VERSION 5.7 ;
  NOWIREEXTENSIONATPIN ON ;
  DIVIDERCHAR "/" ;
  BUSBITCHARS "[]" ;
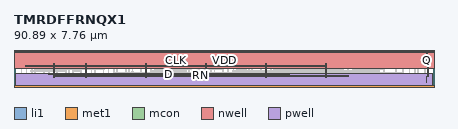
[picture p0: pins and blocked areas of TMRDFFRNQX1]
MACRO TMRDFFRNQX1
  CLASS CORE ;
  FOREIGN TMRDFFRNQX1 ;
  ORIGIN 0.000 0.000 ;
  SIZE 90.890 BY 7.760 ;
  SYMMETRY X Y ;
  SITE unitrh ;
  PIN Q
    DIRECTION OUTPUT ;
    USE SIGNAL ;
    ANTENNADIFFAREA 0.771900 ;
    PORT
      LAYER li1 ;
        RECT 89.210 4.845 89.380 7.200 ;
        RECT 89.210 4.675 89.745 4.845 ;
        RECT 89.575 2.345 89.745 4.675 ;
        RECT 89.205 2.175 89.745 2.345 ;
        RECT 89.205 1.020 89.375 2.175 ;
    END
  END Q
  PIN D
    DIRECTION INPUT ;
    USE SIGNAL ;
    ANTENNAGATEAREA 3.044550 ;
    PORT
      LAYER met1 ;
        RECT 7.405 2.855 7.635 2.885 ;
        RECT 33.305 2.855 33.535 2.885 ;
        RECT 59.205 2.855 59.435 2.885 ;
        RECT 7.375 2.685 59.585 2.855 ;
        RECT 7.405 2.655 7.635 2.685 ;
        RECT 33.305 2.655 33.535 2.685 ;
        RECT 59.205 2.655 59.435 2.685 ;
    END
  END D
  PIN CLK
    DIRECTION INPUT ;
    USE SIGNAL ;
    ANTENNAGATEAREA 6.089100 ;
    PORT
      LAYER met1 ;
        RECT 2.595 4.705 2.825 4.735 ;
        RECT 15.545 4.705 15.775 4.735 ;
        RECT 28.495 4.705 28.725 4.735 ;
        RECT 41.445 4.705 41.675 4.735 ;
        RECT 54.395 4.705 54.625 4.735 ;
        RECT 67.345 4.705 67.575 4.735 ;
        RECT 2.565 4.535 67.605 4.705 ;
        RECT 2.595 4.505 2.825 4.535 ;
        RECT 15.545 4.505 15.775 4.535 ;
        RECT 28.495 4.505 28.725 4.535 ;
        RECT 41.445 4.505 41.675 4.535 ;
        RECT 54.395 4.505 54.625 4.535 ;
        RECT 67.345 4.505 67.575 4.535 ;
    END
    PORT
      LAYER li1 ;
        RECT 15.575 2.095 15.745 5.045 ;
      LAYER mcon ;
        RECT 15.575 4.535 15.745 4.705 ;
    END
    PORT
      LAYER li1 ;
        RECT 28.525 2.095 28.695 5.045 ;
      LAYER mcon ;
        RECT 28.525 4.535 28.695 4.705 ;
    END
    PORT
      LAYER li1 ;
        RECT 41.475 2.095 41.645 5.045 ;
      LAYER mcon ;
        RECT 41.475 4.535 41.645 4.705 ;
    END
    PORT
      LAYER li1 ;
        RECT 54.425 2.095 54.595 5.045 ;
      LAYER mcon ;
        RECT 54.425 4.535 54.595 4.705 ;
    END
    PORT
      LAYER li1 ;
        RECT 67.375 2.095 67.545 5.045 ;
      LAYER mcon ;
        RECT 67.375 4.535 67.545 4.705 ;
    END
  END CLK
  PIN RN
    DIRECTION INPUT ;
    USE SIGNAL ;
    ANTENNAGATEAREA 9.208050 ;
    PORT
      LAYER met1 ;
        RECT 8.515 2.485 8.745 2.515 ;
        RECT 16.655 2.485 16.885 2.515 ;
        RECT 20.355 2.485 20.585 2.515 ;
        RECT 34.415 2.485 34.645 2.515 ;
        RECT 42.555 2.485 42.785 2.515 ;
        RECT 46.255 2.485 46.485 2.515 ;
        RECT 60.315 2.485 60.545 2.515 ;
        RECT 68.455 2.485 68.685 2.515 ;
        RECT 72.155 2.485 72.385 2.515 ;
        RECT 8.485 2.315 72.415 2.485 ;
        RECT 8.515 2.285 8.745 2.315 ;
        RECT 16.655 2.285 16.885 2.315 ;
        RECT 20.355 2.285 20.585 2.315 ;
        RECT 34.415 2.285 34.645 2.315 ;
        RECT 42.555 2.285 42.785 2.315 ;
        RECT 46.255 2.285 46.485 2.315 ;
        RECT 60.315 2.285 60.545 2.315 ;
        RECT 68.455 2.285 68.685 2.315 ;
        RECT 72.155 2.285 72.385 2.315 ;
    END
    PORT
      LAYER li1 ;
        RECT 8.545 2.095 8.715 5.045 ;
      LAYER mcon ;
        RECT 8.545 2.315 8.715 2.485 ;
    END
  END RN
  PIN VDD
    DIRECTION INOUT ;
    USE POWER ;
    SHAPE ABUTMENT ;
    PORT
      LAYER nwell ;
        RECT 0.000 4.110 90.890 7.940 ;
      LAYER met1 ;
        RECT 0.000 7.410 90.890 7.760 ;
    END
  END VDD
  PIN GND
    DIRECTION INOUT ;
    USE GROUND ;
    SHAPE ABUTMENT ;
    PORT
      LAYER pwell ;
        RECT 0.320 0.000 90.570 2.900 ;
      LAYER met1 ;
        RECT 0.000 0.000 90.890 0.350 ;
    END
  END GND
  OBS
      LAYER li1 ;
        RECT 0.000 7.410 90.890 7.760 ;
        RECT 0.320 4.290 0.660 7.410 ;
        RECT 1.495 5.395 1.665 7.410 ;
        RECT 1.935 5.420 2.105 7.200 ;
        RECT 2.375 5.735 2.545 7.410 ;
        RECT 2.815 5.420 2.985 7.200 ;
        RECT 3.255 5.735 3.425 7.410 ;
        RECT 3.695 5.420 3.865 7.200 ;
        RECT 4.135 5.735 4.305 7.410 ;
        RECT 1.935 5.250 4.645 5.420 ;
        RECT 0.320 0.350 0.660 2.900 ;
        RECT 1.515 2.095 1.685 5.045 ;
        RECT 2.625 2.095 2.795 5.045 ;
        RECT 3.735 2.095 3.905 5.045 ;
        RECT 0.995 1.855 1.165 1.935 ;
        RECT 1.965 1.855 2.135 1.935 ;
        RECT 2.935 1.855 3.105 1.935 ;
        RECT 0.995 1.685 3.105 1.855 ;
        RECT 0.995 0.555 1.165 1.685 ;
        RECT 1.480 0.350 1.650 1.310 ;
        RECT 1.965 0.805 2.135 1.685 ;
        RECT 2.935 1.605 3.105 1.685 ;
        RECT 2.455 1.260 2.625 1.340 ;
        RECT 3.505 1.260 3.675 1.935 ;
        RECT 4.475 1.930 4.645 5.250 ;
        RECT 5.130 4.290 5.470 7.410 ;
        RECT 6.305 5.395 6.475 7.410 ;
        RECT 6.745 5.420 6.915 7.200 ;
        RECT 7.185 5.735 7.355 7.410 ;
        RECT 7.625 5.420 7.795 7.200 ;
        RECT 8.065 5.735 8.235 7.410 ;
        RECT 8.505 5.420 8.675 7.200 ;
        RECT 8.945 5.735 9.115 7.410 ;
        RECT 6.745 5.250 9.455 5.420 ;
        RECT 2.455 1.090 3.675 1.260 ;
        RECT 2.455 1.010 2.625 1.090 ;
        RECT 2.935 0.805 3.105 0.885 ;
        RECT 1.965 0.635 3.105 0.805 ;
        RECT 1.965 0.555 2.135 0.635 ;
        RECT 2.935 0.555 3.105 0.635 ;
        RECT 3.505 0.805 3.675 1.090 ;
        RECT 3.990 1.760 4.645 1.930 ;
        RECT 3.990 1.025 4.160 1.760 ;
        RECT 4.475 0.805 4.645 1.575 ;
        RECT 3.505 0.635 4.645 0.805 ;
        RECT 3.505 0.555 3.675 0.635 ;
        RECT 4.475 0.555 4.645 0.635 ;
        RECT 5.130 0.350 5.470 2.900 ;
        RECT 6.325 2.095 6.495 5.045 ;
        RECT 7.435 2.095 7.605 5.045 ;
        RECT 5.805 1.855 5.975 1.935 ;
        RECT 6.775 1.855 6.945 1.935 ;
        RECT 7.745 1.855 7.915 1.935 ;
        RECT 5.805 1.685 7.915 1.855 ;
        RECT 5.805 0.555 5.975 1.685 ;
        RECT 6.290 0.350 6.460 1.310 ;
        RECT 6.775 0.805 6.945 1.685 ;
        RECT 7.745 1.605 7.915 1.685 ;
        RECT 7.265 1.260 7.435 1.340 ;
        RECT 8.315 1.260 8.485 1.935 ;
        RECT 9.285 1.930 9.455 5.250 ;
        RECT 9.940 4.290 10.280 7.410 ;
        RECT 10.815 5.315 10.985 7.410 ;
        RECT 11.255 5.465 11.425 7.200 ;
        RECT 11.695 5.735 11.865 7.410 ;
        RECT 12.135 5.465 12.305 7.200 ;
        RECT 12.575 5.735 12.745 7.410 ;
        RECT 11.255 5.295 12.785 5.465 ;
        RECT 7.265 1.090 8.485 1.260 ;
        RECT 7.265 1.010 7.435 1.090 ;
        RECT 7.745 0.805 7.915 0.885 ;
        RECT 6.775 0.635 7.915 0.805 ;
        RECT 6.775 0.555 6.945 0.635 ;
        RECT 7.745 0.555 7.915 0.635 ;
        RECT 8.315 0.805 8.485 1.090 ;
        RECT 8.800 1.760 9.455 1.930 ;
        RECT 8.800 1.025 8.970 1.760 ;
        RECT 9.285 0.805 9.455 1.575 ;
        RECT 8.315 0.635 9.455 0.805 ;
        RECT 8.315 0.555 8.485 0.635 ;
        RECT 9.285 0.555 9.455 0.635 ;
        RECT 9.940 0.350 10.280 2.900 ;
        RECT 11.135 2.095 11.305 5.045 ;
        RECT 11.905 4.890 12.075 5.045 ;
        RECT 11.875 4.715 12.075 4.890 ;
        RECT 11.875 2.095 12.045 4.715 ;
        RECT 10.720 1.845 10.890 1.925 ;
        RECT 11.690 1.845 11.860 1.925 ;
        RECT 12.615 1.920 12.785 5.295 ;
        RECT 13.270 4.290 13.610 7.410 ;
        RECT 14.445 5.395 14.615 7.410 ;
        RECT 14.885 5.420 15.055 7.200 ;
        RECT 15.325 5.735 15.495 7.410 ;
        RECT 15.765 5.420 15.935 7.200 ;
        RECT 16.205 5.735 16.375 7.410 ;
        RECT 16.645 5.420 16.815 7.200 ;
        RECT 17.085 5.735 17.255 7.410 ;
        RECT 14.885 5.250 17.595 5.420 ;
        RECT 10.720 1.675 11.860 1.845 ;
        RECT 10.720 0.545 10.890 1.675 ;
        RECT 11.205 0.350 11.375 1.300 ;
        RECT 11.690 0.795 11.860 1.675 ;
        RECT 12.175 1.750 12.785 1.920 ;
        RECT 12.175 1.015 12.345 1.750 ;
        RECT 12.660 0.795 12.830 1.565 ;
        RECT 11.690 0.625 12.830 0.795 ;
        RECT 11.690 0.545 11.860 0.625 ;
        RECT 12.660 0.545 12.830 0.625 ;
        RECT 13.270 0.350 13.610 2.900 ;
        RECT 14.465 2.095 14.635 5.045 ;
        RECT 16.685 2.095 16.855 5.045 ;
        RECT 13.945 1.855 14.115 1.935 ;
        RECT 14.915 1.855 15.085 1.935 ;
        RECT 15.885 1.855 16.055 1.935 ;
        RECT 13.945 1.685 16.055 1.855 ;
        RECT 13.945 0.555 14.115 1.685 ;
        RECT 14.430 0.350 14.600 1.310 ;
        RECT 14.915 0.805 15.085 1.685 ;
        RECT 15.885 1.605 16.055 1.685 ;
        RECT 15.405 1.260 15.575 1.340 ;
        RECT 16.455 1.260 16.625 1.935 ;
        RECT 17.425 1.930 17.595 5.250 ;
        RECT 18.080 4.290 18.420 7.410 ;
        RECT 19.255 5.395 19.425 7.410 ;
        RECT 19.695 5.420 19.865 7.200 ;
        RECT 20.135 5.735 20.305 7.410 ;
        RECT 20.575 5.420 20.745 7.200 ;
        RECT 21.015 5.735 21.185 7.410 ;
        RECT 21.455 5.420 21.625 7.200 ;
        RECT 21.895 5.735 22.065 7.410 ;
        RECT 19.695 5.250 22.405 5.420 ;
        RECT 15.405 1.090 16.625 1.260 ;
        RECT 15.405 1.010 15.575 1.090 ;
        RECT 15.885 0.805 16.055 0.885 ;
        RECT 14.915 0.635 16.055 0.805 ;
        RECT 14.915 0.555 15.085 0.635 ;
        RECT 15.885 0.555 16.055 0.635 ;
        RECT 16.455 0.805 16.625 1.090 ;
        RECT 16.940 1.760 17.595 1.930 ;
        RECT 16.940 1.025 17.110 1.760 ;
        RECT 17.425 0.805 17.595 1.575 ;
        RECT 16.455 0.635 17.595 0.805 ;
        RECT 16.455 0.555 16.625 0.635 ;
        RECT 17.425 0.555 17.595 0.635 ;
        RECT 18.080 0.350 18.420 2.900 ;
        RECT 19.275 2.095 19.445 5.045 ;
        RECT 20.385 2.095 20.555 5.045 ;
        RECT 21.495 2.095 21.665 5.045 ;
        RECT 18.755 1.855 18.925 1.935 ;
        RECT 19.725 1.855 19.895 1.935 ;
        RECT 20.695 1.855 20.865 1.935 ;
        RECT 18.755 1.685 20.865 1.855 ;
        RECT 18.755 0.555 18.925 1.685 ;
        RECT 19.240 0.350 19.410 1.310 ;
        RECT 19.725 0.805 19.895 1.685 ;
        RECT 20.695 1.605 20.865 1.685 ;
        RECT 20.215 1.260 20.385 1.340 ;
        RECT 21.265 1.260 21.435 1.935 ;
        RECT 22.235 1.930 22.405 5.250 ;
        RECT 22.890 4.290 23.230 7.410 ;
        RECT 23.765 5.315 23.935 7.410 ;
        RECT 24.205 5.465 24.375 7.200 ;
        RECT 24.645 5.735 24.815 7.410 ;
        RECT 25.085 5.465 25.255 7.200 ;
        RECT 25.525 5.735 25.695 7.410 ;
        RECT 24.205 5.295 25.735 5.465 ;
        RECT 20.215 1.090 21.435 1.260 ;
        RECT 20.215 1.010 20.385 1.090 ;
        RECT 20.695 0.805 20.865 0.885 ;
        RECT 19.725 0.635 20.865 0.805 ;
        RECT 19.725 0.555 19.895 0.635 ;
        RECT 20.695 0.555 20.865 0.635 ;
        RECT 21.265 0.805 21.435 1.090 ;
        RECT 21.750 1.760 22.405 1.930 ;
        RECT 21.750 1.025 21.920 1.760 ;
        RECT 22.235 0.805 22.405 1.575 ;
        RECT 21.265 0.635 22.405 0.805 ;
        RECT 21.265 0.555 21.435 0.635 ;
        RECT 22.235 0.555 22.405 0.635 ;
        RECT 22.890 0.350 23.230 2.900 ;
        RECT 24.085 2.095 24.255 5.045 ;
        RECT 24.855 4.890 25.025 5.045 ;
        RECT 24.825 4.715 25.025 4.890 ;
        RECT 24.825 2.095 24.995 4.715 ;
        RECT 23.670 1.845 23.840 1.925 ;
        RECT 24.640 1.845 24.810 1.925 ;
        RECT 25.565 1.920 25.735 5.295 ;
        RECT 26.220 4.290 26.560 7.410 ;
        RECT 27.395 5.395 27.565 7.410 ;
        RECT 27.835 5.420 28.005 7.200 ;
        RECT 28.275 5.735 28.445 7.410 ;
        RECT 28.715 5.420 28.885 7.200 ;
        RECT 29.155 5.735 29.325 7.410 ;
        RECT 29.595 5.420 29.765 7.200 ;
        RECT 30.035 5.735 30.205 7.410 ;
        RECT 27.835 5.250 30.545 5.420 ;
        RECT 23.670 1.675 24.810 1.845 ;
        RECT 23.670 0.545 23.840 1.675 ;
        RECT 24.155 0.350 24.325 1.300 ;
        RECT 24.640 0.795 24.810 1.675 ;
        RECT 25.125 1.750 25.735 1.920 ;
        RECT 25.125 1.015 25.295 1.750 ;
        RECT 25.610 0.795 25.780 1.565 ;
        RECT 24.640 0.625 25.780 0.795 ;
        RECT 24.640 0.545 24.810 0.625 ;
        RECT 25.610 0.545 25.780 0.625 ;
        RECT 26.220 0.350 26.560 2.900 ;
        RECT 27.415 2.095 27.585 5.045 ;
        RECT 29.635 2.095 29.805 5.045 ;
        RECT 26.895 1.855 27.065 1.935 ;
        RECT 27.865 1.855 28.035 1.935 ;
        RECT 28.835 1.855 29.005 1.935 ;
        RECT 26.895 1.685 29.005 1.855 ;
        RECT 26.895 0.555 27.065 1.685 ;
        RECT 27.380 0.350 27.550 1.310 ;
        RECT 27.865 0.805 28.035 1.685 ;
        RECT 28.835 1.605 29.005 1.685 ;
        RECT 28.355 1.260 28.525 1.340 ;
        RECT 29.405 1.260 29.575 1.935 ;
        RECT 30.375 1.930 30.545 5.250 ;
        RECT 31.030 4.290 31.370 7.410 ;
        RECT 32.205 5.395 32.375 7.410 ;
        RECT 32.645 5.420 32.815 7.200 ;
        RECT 33.085 5.735 33.255 7.410 ;
        RECT 33.525 5.420 33.695 7.200 ;
        RECT 33.965 5.735 34.135 7.410 ;
        RECT 34.405 5.420 34.575 7.200 ;
        RECT 34.845 5.735 35.015 7.410 ;
        RECT 32.645 5.250 35.355 5.420 ;
        RECT 28.355 1.090 29.575 1.260 ;
        RECT 28.355 1.010 28.525 1.090 ;
        RECT 28.835 0.805 29.005 0.885 ;
        RECT 27.865 0.635 29.005 0.805 ;
        RECT 27.865 0.555 28.035 0.635 ;
        RECT 28.835 0.555 29.005 0.635 ;
        RECT 29.405 0.805 29.575 1.090 ;
        RECT 29.890 1.760 30.545 1.930 ;
        RECT 29.890 1.025 30.060 1.760 ;
        RECT 30.375 0.805 30.545 1.575 ;
        RECT 29.405 0.635 30.545 0.805 ;
        RECT 29.405 0.555 29.575 0.635 ;
        RECT 30.375 0.555 30.545 0.635 ;
        RECT 31.030 0.350 31.370 2.900 ;
        RECT 32.225 2.095 32.395 5.045 ;
        RECT 33.335 2.095 33.505 5.045 ;
        RECT 34.445 2.095 34.615 5.045 ;
        RECT 31.705 1.855 31.875 1.935 ;
        RECT 32.675 1.855 32.845 1.935 ;
        RECT 33.645 1.855 33.815 1.935 ;
        RECT 31.705 1.685 33.815 1.855 ;
        RECT 31.705 0.555 31.875 1.685 ;
        RECT 32.190 0.350 32.360 1.310 ;
        RECT 32.675 0.805 32.845 1.685 ;
        RECT 33.645 1.605 33.815 1.685 ;
        RECT 33.165 1.260 33.335 1.340 ;
        RECT 34.215 1.260 34.385 1.935 ;
        RECT 35.185 1.930 35.355 5.250 ;
        RECT 35.840 4.290 36.180 7.410 ;
        RECT 36.715 5.315 36.885 7.410 ;
        RECT 37.155 5.465 37.325 7.200 ;
        RECT 37.595 5.735 37.765 7.410 ;
        RECT 38.035 5.465 38.205 7.200 ;
        RECT 38.475 5.735 38.645 7.410 ;
        RECT 37.155 5.295 38.685 5.465 ;
        RECT 33.165 1.090 34.385 1.260 ;
        RECT 33.165 1.010 33.335 1.090 ;
        RECT 33.645 0.805 33.815 0.885 ;
        RECT 32.675 0.635 33.815 0.805 ;
        RECT 32.675 0.555 32.845 0.635 ;
        RECT 33.645 0.555 33.815 0.635 ;
        RECT 34.215 0.805 34.385 1.090 ;
        RECT 34.700 1.760 35.355 1.930 ;
        RECT 34.700 1.025 34.870 1.760 ;
        RECT 35.185 0.805 35.355 1.575 ;
        RECT 34.215 0.635 35.355 0.805 ;
        RECT 34.215 0.555 34.385 0.635 ;
        RECT 35.185 0.555 35.355 0.635 ;
        RECT 35.840 0.350 36.180 2.900 ;
        RECT 37.035 2.095 37.205 5.045 ;
        RECT 37.805 4.890 37.975 5.045 ;
        RECT 37.775 4.715 37.975 4.890 ;
        RECT 37.775 2.095 37.945 4.715 ;
        RECT 36.620 1.845 36.790 1.925 ;
        RECT 37.590 1.845 37.760 1.925 ;
        RECT 38.515 1.920 38.685 5.295 ;
        RECT 39.170 4.290 39.510 7.410 ;
        RECT 40.345 5.395 40.515 7.410 ;
        RECT 40.785 5.420 40.955 7.200 ;
        RECT 41.225 5.735 41.395 7.410 ;
        RECT 41.665 5.420 41.835 7.200 ;
        RECT 42.105 5.735 42.275 7.410 ;
        RECT 42.545 5.420 42.715 7.200 ;
        RECT 42.985 5.735 43.155 7.410 ;
        RECT 40.785 5.250 43.495 5.420 ;
        RECT 36.620 1.675 37.760 1.845 ;
        RECT 36.620 0.545 36.790 1.675 ;
        RECT 37.105 0.350 37.275 1.300 ;
        RECT 37.590 0.795 37.760 1.675 ;
        RECT 38.075 1.750 38.685 1.920 ;
        RECT 38.075 1.015 38.245 1.750 ;
        RECT 38.560 0.795 38.730 1.565 ;
        RECT 37.590 0.625 38.730 0.795 ;
        RECT 37.590 0.545 37.760 0.625 ;
        RECT 38.560 0.545 38.730 0.625 ;
        RECT 39.170 0.350 39.510 2.900 ;
        RECT 40.365 2.095 40.535 5.045 ;
        RECT 42.585 2.095 42.755 5.045 ;
        RECT 39.845 1.855 40.015 1.935 ;
        RECT 40.815 1.855 40.985 1.935 ;
        RECT 41.785 1.855 41.955 1.935 ;
        RECT 39.845 1.685 41.955 1.855 ;
        RECT 39.845 0.555 40.015 1.685 ;
        RECT 40.330 0.350 40.500 1.310 ;
        RECT 40.815 0.805 40.985 1.685 ;
        RECT 41.785 1.605 41.955 1.685 ;
        RECT 41.305 1.260 41.475 1.340 ;
        RECT 42.355 1.260 42.525 1.935 ;
        RECT 43.325 1.930 43.495 5.250 ;
        RECT 43.980 4.290 44.320 7.410 ;
        RECT 45.155 5.395 45.325 7.410 ;
        RECT 45.595 5.420 45.765 7.200 ;
        RECT 46.035 5.735 46.205 7.410 ;
        RECT 46.475 5.420 46.645 7.200 ;
        RECT 46.915 5.735 47.085 7.410 ;
        RECT 47.355 5.420 47.525 7.200 ;
        RECT 47.795 5.735 47.965 7.410 ;
        RECT 45.595 5.250 48.305 5.420 ;
        RECT 41.305 1.090 42.525 1.260 ;
        RECT 41.305 1.010 41.475 1.090 ;
        RECT 41.785 0.805 41.955 0.885 ;
        RECT 40.815 0.635 41.955 0.805 ;
        RECT 40.815 0.555 40.985 0.635 ;
        RECT 41.785 0.555 41.955 0.635 ;
        RECT 42.355 0.805 42.525 1.090 ;
        RECT 42.840 1.760 43.495 1.930 ;
        RECT 42.840 1.025 43.010 1.760 ;
        RECT 43.325 0.805 43.495 1.575 ;
        RECT 42.355 0.635 43.495 0.805 ;
        RECT 42.355 0.555 42.525 0.635 ;
        RECT 43.325 0.555 43.495 0.635 ;
        RECT 43.980 0.350 44.320 2.900 ;
        RECT 45.175 2.095 45.345 5.045 ;
        RECT 46.285 2.095 46.455 5.045 ;
        RECT 47.395 2.095 47.565 5.045 ;
        RECT 44.655 1.855 44.825 1.935 ;
        RECT 45.625 1.855 45.795 1.935 ;
        RECT 46.595 1.855 46.765 1.935 ;
        RECT 44.655 1.685 46.765 1.855 ;
        RECT 44.655 0.555 44.825 1.685 ;
        RECT 45.140 0.350 45.310 1.310 ;
        RECT 45.625 0.805 45.795 1.685 ;
        RECT 46.595 1.605 46.765 1.685 ;
        RECT 46.115 1.260 46.285 1.340 ;
        RECT 47.165 1.260 47.335 1.935 ;
        RECT 48.135 1.930 48.305 5.250 ;
        RECT 48.790 4.290 49.130 7.410 ;
        RECT 49.665 5.315 49.835 7.410 ;
        RECT 50.105 5.465 50.275 7.200 ;
        RECT 50.545 5.735 50.715 7.410 ;
        RECT 50.985 5.465 51.155 7.200 ;
        RECT 51.425 5.735 51.595 7.410 ;
        RECT 50.105 5.295 51.635 5.465 ;
        RECT 46.115 1.090 47.335 1.260 ;
        RECT 46.115 1.010 46.285 1.090 ;
        RECT 46.595 0.805 46.765 0.885 ;
        RECT 45.625 0.635 46.765 0.805 ;
        RECT 45.625 0.555 45.795 0.635 ;
        RECT 46.595 0.555 46.765 0.635 ;
        RECT 47.165 0.805 47.335 1.090 ;
        RECT 47.650 1.760 48.305 1.930 ;
        RECT 47.650 1.025 47.820 1.760 ;
        RECT 48.135 0.805 48.305 1.575 ;
        RECT 47.165 0.635 48.305 0.805 ;
        RECT 47.165 0.555 47.335 0.635 ;
        RECT 48.135 0.555 48.305 0.635 ;
        RECT 48.790 0.350 49.130 2.900 ;
        RECT 49.985 2.095 50.155 5.045 ;
        RECT 50.755 4.890 50.925 5.045 ;
        RECT 50.725 4.715 50.925 4.890 ;
        RECT 50.725 2.095 50.895 4.715 ;
        RECT 49.570 1.845 49.740 1.925 ;
        RECT 50.540 1.845 50.710 1.925 ;
        RECT 51.465 1.920 51.635 5.295 ;
        RECT 52.120 4.290 52.460 7.410 ;
        RECT 53.295 5.395 53.465 7.410 ;
        RECT 53.735 5.420 53.905 7.200 ;
        RECT 54.175 5.735 54.345 7.410 ;
        RECT 54.615 5.420 54.785 7.200 ;
        RECT 55.055 5.735 55.225 7.410 ;
        RECT 55.495 5.420 55.665 7.200 ;
        RECT 55.935 5.735 56.105 7.410 ;
        RECT 53.735 5.250 56.445 5.420 ;
        RECT 49.570 1.675 50.710 1.845 ;
        RECT 49.570 0.545 49.740 1.675 ;
        RECT 50.055 0.350 50.225 1.300 ;
        RECT 50.540 0.795 50.710 1.675 ;
        RECT 51.025 1.750 51.635 1.920 ;
        RECT 51.025 1.015 51.195 1.750 ;
        RECT 51.510 0.795 51.680 1.565 ;
        RECT 50.540 0.625 51.680 0.795 ;
        RECT 50.540 0.545 50.710 0.625 ;
        RECT 51.510 0.545 51.680 0.625 ;
        RECT 52.120 0.350 52.460 2.900 ;
        RECT 53.315 2.095 53.485 5.045 ;
        RECT 55.535 2.095 55.705 5.045 ;
        RECT 52.795 1.855 52.965 1.935 ;
        RECT 53.765 1.855 53.935 1.935 ;
        RECT 54.735 1.855 54.905 1.935 ;
        RECT 52.795 1.685 54.905 1.855 ;
        RECT 52.795 0.555 52.965 1.685 ;
        RECT 53.280 0.350 53.450 1.310 ;
        RECT 53.765 0.805 53.935 1.685 ;
        RECT 54.735 1.605 54.905 1.685 ;
        RECT 54.255 1.260 54.425 1.340 ;
        RECT 55.305 1.260 55.475 1.935 ;
        RECT 56.275 1.930 56.445 5.250 ;
        RECT 56.930 4.290 57.270 7.410 ;
        RECT 58.105 5.395 58.275 7.410 ;
        RECT 58.545 5.420 58.715 7.200 ;
        RECT 58.985 5.735 59.155 7.410 ;
        RECT 59.425 5.420 59.595 7.200 ;
        RECT 59.865 5.735 60.035 7.410 ;
        RECT 60.305 5.420 60.475 7.200 ;
        RECT 60.745 5.735 60.915 7.410 ;
        RECT 58.545 5.250 61.255 5.420 ;
        RECT 54.255 1.090 55.475 1.260 ;
        RECT 54.255 1.010 54.425 1.090 ;
        RECT 54.735 0.805 54.905 0.885 ;
        RECT 53.765 0.635 54.905 0.805 ;
        RECT 53.765 0.555 53.935 0.635 ;
        RECT 54.735 0.555 54.905 0.635 ;
        RECT 55.305 0.805 55.475 1.090 ;
        RECT 55.790 1.760 56.445 1.930 ;
        RECT 55.790 1.025 55.960 1.760 ;
        RECT 56.275 0.805 56.445 1.575 ;
        RECT 55.305 0.635 56.445 0.805 ;
        RECT 55.305 0.555 55.475 0.635 ;
        RECT 56.275 0.555 56.445 0.635 ;
        RECT 56.930 0.350 57.270 2.900 ;
        RECT 58.125 2.095 58.295 5.045 ;
        RECT 59.235 2.095 59.405 5.045 ;
        RECT 60.345 2.095 60.515 5.045 ;
        RECT 57.605 1.855 57.775 1.935 ;
        RECT 58.575 1.855 58.745 1.935 ;
        RECT 59.545 1.855 59.715 1.935 ;
        RECT 57.605 1.685 59.715 1.855 ;
        RECT 57.605 0.555 57.775 1.685 ;
        RECT 58.090 0.350 58.260 1.310 ;
        RECT 58.575 0.805 58.745 1.685 ;
        RECT 59.545 1.605 59.715 1.685 ;
        RECT 59.065 1.260 59.235 1.340 ;
        RECT 60.115 1.260 60.285 1.935 ;
        RECT 61.085 1.930 61.255 5.250 ;
        RECT 61.740 4.290 62.080 7.410 ;
        RECT 62.615 5.315 62.785 7.410 ;
        RECT 63.055 5.465 63.225 7.200 ;
        RECT 63.495 5.735 63.665 7.410 ;
        RECT 63.935 5.465 64.105 7.200 ;
        RECT 64.375 5.735 64.545 7.410 ;
        RECT 63.055 5.295 64.585 5.465 ;
        RECT 59.065 1.090 60.285 1.260 ;
        RECT 59.065 1.010 59.235 1.090 ;
        RECT 59.545 0.805 59.715 0.885 ;
        RECT 58.575 0.635 59.715 0.805 ;
        RECT 58.575 0.555 58.745 0.635 ;
        RECT 59.545 0.555 59.715 0.635 ;
        RECT 60.115 0.805 60.285 1.090 ;
        RECT 60.600 1.760 61.255 1.930 ;
        RECT 60.600 1.025 60.770 1.760 ;
        RECT 61.085 0.805 61.255 1.575 ;
        RECT 60.115 0.635 61.255 0.805 ;
        RECT 60.115 0.555 60.285 0.635 ;
        RECT 61.085 0.555 61.255 0.635 ;
        RECT 61.740 0.350 62.080 2.900 ;
        RECT 62.935 2.095 63.105 5.045 ;
        RECT 63.705 4.890 63.875 5.045 ;
        RECT 63.675 4.715 63.875 4.890 ;
        RECT 63.675 2.095 63.845 4.715 ;
        RECT 62.520 1.845 62.690 1.925 ;
        RECT 63.490 1.845 63.660 1.925 ;
        RECT 64.415 1.920 64.585 5.295 ;
        RECT 65.070 4.290 65.410 7.410 ;
        RECT 66.245 5.395 66.415 7.410 ;
        RECT 66.685 5.420 66.855 7.200 ;
        RECT 67.125 5.735 67.295 7.410 ;
        RECT 67.565 5.420 67.735 7.200 ;
        RECT 68.005 5.735 68.175 7.410 ;
        RECT 68.445 5.420 68.615 7.200 ;
        RECT 68.885 5.735 69.055 7.410 ;
        RECT 66.685 5.250 69.395 5.420 ;
        RECT 62.520 1.675 63.660 1.845 ;
        RECT 62.520 0.545 62.690 1.675 ;
        RECT 63.005 0.350 63.175 1.300 ;
        RECT 63.490 0.795 63.660 1.675 ;
        RECT 63.975 1.750 64.585 1.920 ;
        RECT 63.975 1.015 64.145 1.750 ;
        RECT 64.460 0.795 64.630 1.565 ;
        RECT 63.490 0.625 64.630 0.795 ;
        RECT 63.490 0.545 63.660 0.625 ;
        RECT 64.460 0.545 64.630 0.625 ;
        RECT 65.070 0.350 65.410 2.900 ;
        RECT 66.265 2.095 66.435 5.045 ;
        RECT 68.485 2.095 68.655 5.045 ;
        RECT 65.745 1.855 65.915 1.935 ;
        RECT 66.715 1.855 66.885 1.935 ;
        RECT 67.685 1.855 67.855 1.935 ;
        RECT 65.745 1.685 67.855 1.855 ;
        RECT 65.745 0.555 65.915 1.685 ;
        RECT 66.230 0.350 66.400 1.310 ;
        RECT 66.715 0.805 66.885 1.685 ;
        RECT 67.685 1.605 67.855 1.685 ;
        RECT 67.205 1.260 67.375 1.340 ;
        RECT 68.255 1.260 68.425 1.935 ;
        RECT 69.225 1.930 69.395 5.250 ;
        RECT 69.880 4.290 70.220 7.410 ;
        RECT 71.055 5.395 71.225 7.410 ;
        RECT 71.495 5.420 71.665 7.200 ;
        RECT 71.935 5.735 72.105 7.410 ;
        RECT 72.375 5.420 72.545 7.200 ;
        RECT 72.815 5.735 72.985 7.410 ;
        RECT 73.255 5.420 73.425 7.200 ;
        RECT 73.695 5.735 73.865 7.410 ;
        RECT 71.495 5.250 74.205 5.420 ;
        RECT 67.205 1.090 68.425 1.260 ;
        RECT 67.205 1.010 67.375 1.090 ;
        RECT 67.685 0.805 67.855 0.885 ;
        RECT 66.715 0.635 67.855 0.805 ;
        RECT 66.715 0.555 66.885 0.635 ;
        RECT 67.685 0.555 67.855 0.635 ;
        RECT 68.255 0.805 68.425 1.090 ;
        RECT 68.740 1.760 69.395 1.930 ;
        RECT 68.740 1.025 68.910 1.760 ;
        RECT 69.225 0.805 69.395 1.575 ;
        RECT 68.255 0.635 69.395 0.805 ;
        RECT 68.255 0.555 68.425 0.635 ;
        RECT 69.225 0.555 69.395 0.635 ;
        RECT 69.880 0.350 70.220 2.900 ;
        RECT 71.075 2.095 71.245 5.045 ;
        RECT 72.185 2.095 72.355 5.045 ;
        RECT 73.295 2.095 73.465 5.045 ;
        RECT 70.555 1.855 70.725 1.935 ;
        RECT 71.525 1.855 71.695 1.935 ;
        RECT 72.495 1.855 72.665 1.935 ;
        RECT 70.555 1.685 72.665 1.855 ;
        RECT 70.555 0.555 70.725 1.685 ;
        RECT 71.040 0.350 71.210 1.310 ;
        RECT 71.525 0.805 71.695 1.685 ;
        RECT 72.495 1.605 72.665 1.685 ;
        RECT 72.015 1.260 72.185 1.340 ;
        RECT 73.065 1.260 73.235 1.935 ;
        RECT 74.035 1.930 74.205 5.250 ;
        RECT 74.690 4.290 75.030 7.410 ;
        RECT 75.565 5.315 75.735 7.410 ;
        RECT 76.005 5.465 76.175 7.200 ;
        RECT 76.445 5.735 76.615 7.410 ;
        RECT 76.885 5.465 77.055 7.200 ;
        RECT 77.325 5.735 77.495 7.410 ;
        RECT 76.005 5.295 77.535 5.465 ;
        RECT 72.015 1.090 73.235 1.260 ;
        RECT 72.015 1.010 72.185 1.090 ;
        RECT 72.495 0.805 72.665 0.885 ;
        RECT 71.525 0.635 72.665 0.805 ;
        RECT 71.525 0.555 71.695 0.635 ;
        RECT 72.495 0.555 72.665 0.635 ;
        RECT 73.065 0.805 73.235 1.090 ;
        RECT 73.550 1.760 74.205 1.930 ;
        RECT 73.550 1.025 73.720 1.760 ;
        RECT 74.035 0.805 74.205 1.575 ;
        RECT 73.065 0.635 74.205 0.805 ;
        RECT 73.065 0.555 73.235 0.635 ;
        RECT 74.035 0.555 74.205 0.635 ;
        RECT 74.690 0.350 75.030 2.900 ;
        RECT 75.885 2.095 76.055 5.045 ;
        RECT 76.655 4.890 76.825 5.045 ;
        RECT 76.625 4.715 76.825 4.890 ;
        RECT 76.625 2.095 76.795 4.715 ;
        RECT 75.470 1.845 75.640 1.925 ;
        RECT 76.440 1.845 76.610 1.925 ;
        RECT 77.365 1.920 77.535 5.295 ;
        RECT 78.020 4.290 78.360 7.410 ;
        RECT 78.895 5.305 79.065 7.410 ;
        RECT 79.335 7.005 79.515 7.175 ;
        RECT 79.335 5.475 79.505 7.005 ;
        RECT 79.775 5.735 79.945 7.410 ;
        RECT 80.215 5.475 80.385 7.175 ;
        RECT 79.335 5.305 80.385 5.475 ;
        RECT 80.655 5.305 80.825 7.410 ;
        RECT 80.215 5.225 80.385 5.305 ;
        RECT 75.470 1.675 76.610 1.845 ;
        RECT 75.470 0.545 75.640 1.675 ;
        RECT 75.955 0.350 76.125 1.300 ;
        RECT 76.440 0.795 76.610 1.675 ;
        RECT 76.925 1.750 77.535 1.920 ;
        RECT 76.925 1.015 77.095 1.750 ;
        RECT 77.410 0.795 77.580 1.565 ;
        RECT 76.440 0.625 77.580 0.795 ;
        RECT 76.440 0.545 76.610 0.625 ;
        RECT 77.410 0.545 77.580 0.625 ;
        RECT 78.020 0.350 78.360 2.900 ;
        RECT 78.845 2.095 79.015 5.050 ;
        RECT 79.995 4.890 80.165 5.050 ;
        RECT 79.955 4.720 80.165 4.890 ;
        RECT 79.955 2.095 80.125 4.720 ;
        RECT 81.350 4.290 81.690 7.410 ;
        RECT 82.215 7.005 84.145 7.175 ;
        RECT 82.215 5.225 82.385 7.005 ;
        RECT 82.655 5.475 82.825 6.745 ;
        RECT 83.095 5.735 83.265 7.005 ;
        RECT 83.535 5.475 83.705 6.745 ;
        RECT 83.975 5.555 84.145 7.005 ;
        RECT 82.655 5.305 83.705 5.475 ;
        RECT 83.535 5.225 83.705 5.305 ;
        RECT 78.800 1.845 78.970 1.925 ;
        RECT 79.770 1.845 79.940 1.925 ;
        RECT 78.800 1.675 79.940 1.845 ;
        RECT 78.800 0.545 78.970 1.675 ;
        RECT 79.285 0.350 79.455 1.300 ;
        RECT 79.770 0.795 79.940 1.675 ;
        RECT 80.255 1.350 80.425 1.525 ;
        RECT 80.250 1.195 80.425 1.350 ;
        RECT 80.250 1.015 80.420 1.195 ;
        RECT 80.740 0.795 80.910 1.925 ;
        RECT 79.770 0.625 80.910 0.795 ;
        RECT 79.770 0.545 79.940 0.625 ;
        RECT 80.740 0.545 80.910 0.625 ;
        RECT 81.350 0.350 81.690 2.900 ;
        RECT 82.545 2.095 82.715 5.050 ;
        RECT 84.025 2.095 84.195 5.050 ;
        RECT 84.680 4.290 85.020 7.410 ;
        RECT 85.555 7.005 87.485 7.175 ;
        RECT 85.555 5.225 85.725 7.005 ;
        RECT 85.995 5.475 86.165 6.745 ;
        RECT 86.435 5.735 86.605 7.005 ;
        RECT 86.875 5.475 87.045 6.745 ;
        RECT 87.315 5.735 87.485 7.005 ;
        RECT 85.995 5.305 87.525 5.475 ;
        RECT 82.130 1.845 82.300 1.925 ;
        RECT 83.100 1.845 83.270 1.925 ;
        RECT 82.130 1.675 83.270 1.845 ;
        RECT 82.130 0.545 82.300 1.675 ;
        RECT 82.615 0.350 82.785 1.300 ;
        RECT 83.100 0.795 83.270 1.675 ;
        RECT 83.585 1.015 83.755 1.525 ;
        RECT 84.070 0.795 84.240 1.925 ;
        RECT 83.100 0.625 84.240 0.795 ;
        RECT 83.100 0.545 83.270 0.625 ;
        RECT 84.070 0.545 84.240 0.625 ;
        RECT 84.680 0.350 85.020 2.900 ;
        RECT 85.505 2.095 85.675 5.050 ;
        RECT 86.615 4.720 86.805 5.050 ;
        RECT 86.615 2.095 86.785 4.720 ;
        RECT 85.460 1.845 85.630 1.925 ;
        RECT 86.430 1.845 86.600 1.925 ;
        RECT 87.355 1.910 87.525 5.305 ;
        RECT 88.010 4.290 88.350 7.410 ;
        RECT 88.770 5.365 88.940 7.410 ;
        RECT 89.650 5.365 89.820 7.410 ;
        RECT 85.460 1.675 86.600 1.845 ;
        RECT 85.460 0.545 85.630 1.675 ;
        RECT 85.945 0.350 86.115 1.300 ;
        RECT 86.430 0.795 86.600 1.675 ;
        RECT 86.915 1.740 87.525 1.910 ;
        RECT 86.915 1.015 87.085 1.740 ;
        RECT 87.400 0.795 87.570 1.570 ;
        RECT 86.430 0.625 87.570 0.795 ;
        RECT 86.430 0.545 86.600 0.625 ;
        RECT 87.400 0.545 87.570 0.625 ;
        RECT 88.010 0.350 88.350 2.900 ;
        RECT 88.835 2.100 89.005 5.045 ;
        RECT 90.230 4.290 90.570 7.410 ;
        RECT 88.725 0.800 88.895 1.930 ;
        RECT 89.695 0.800 89.865 1.930 ;
        RECT 88.725 0.630 89.865 0.800 ;
        RECT 88.725 0.350 88.895 0.630 ;
        RECT 89.210 0.350 89.380 0.630 ;
        RECT 89.695 0.350 89.865 0.630 ;
        RECT 90.230 0.350 90.570 2.900 ;
        RECT 0.000 0.000 90.890 0.350 ;
      LAYER mcon ;
        RECT 0.775 7.495 0.945 7.665 ;
        RECT 1.145 7.495 1.315 7.665 ;
        RECT 1.515 7.495 1.685 7.665 ;
        RECT 1.885 7.495 2.055 7.665 ;
        RECT 2.255 7.495 2.425 7.665 ;
        RECT 2.625 7.495 2.795 7.665 ;
        RECT 2.995 7.495 3.165 7.665 ;
        RECT 3.365 7.495 3.535 7.665 ;
        RECT 3.735 7.495 3.905 7.665 ;
        RECT 4.105 7.495 4.275 7.665 ;
        RECT 4.475 7.495 4.645 7.665 ;
        RECT 4.845 7.495 5.015 7.665 ;
        RECT 5.585 7.495 5.755 7.665 ;
        RECT 5.955 7.495 6.125 7.665 ;
        RECT 6.325 7.495 6.495 7.665 ;
        RECT 6.695 7.495 6.865 7.665 ;
        RECT 7.065 7.495 7.235 7.665 ;
        RECT 7.435 7.495 7.605 7.665 ;
        RECT 7.805 7.495 7.975 7.665 ;
        RECT 8.175 7.495 8.345 7.665 ;
        RECT 8.545 7.495 8.715 7.665 ;
        RECT 8.915 7.495 9.085 7.665 ;
        RECT 9.285 7.495 9.455 7.665 ;
        RECT 9.655 7.495 9.825 7.665 ;
        RECT 10.395 7.495 10.565 7.665 ;
        RECT 10.765 7.495 10.935 7.665 ;
        RECT 11.135 7.495 11.305 7.665 ;
        RECT 11.505 7.495 11.675 7.665 ;
        RECT 11.875 7.495 12.045 7.665 ;
        RECT 12.245 7.495 12.415 7.665 ;
        RECT 12.615 7.495 12.785 7.665 ;
        RECT 12.985 7.495 13.155 7.665 ;
        RECT 13.725 7.495 13.895 7.665 ;
        RECT 14.095 7.495 14.265 7.665 ;
        RECT 14.465 7.495 14.635 7.665 ;
        RECT 14.835 7.495 15.005 7.665 ;
        RECT 15.205 7.495 15.375 7.665 ;
        RECT 15.575 7.495 15.745 7.665 ;
        RECT 15.945 7.495 16.115 7.665 ;
        RECT 16.315 7.495 16.485 7.665 ;
        RECT 16.685 7.495 16.855 7.665 ;
        RECT 17.055 7.495 17.225 7.665 ;
        RECT 17.425 7.495 17.595 7.665 ;
        RECT 17.795 7.495 17.965 7.665 ;
        RECT 18.535 7.495 18.705 7.665 ;
        RECT 18.905 7.495 19.075 7.665 ;
        RECT 19.275 7.495 19.445 7.665 ;
        RECT 19.645 7.495 19.815 7.665 ;
        RECT 20.015 7.495 20.185 7.665 ;
        RECT 20.385 7.495 20.555 7.665 ;
        RECT 20.755 7.495 20.925 7.665 ;
        RECT 21.125 7.495 21.295 7.665 ;
        RECT 21.495 7.495 21.665 7.665 ;
        RECT 21.865 7.495 22.035 7.665 ;
        RECT 22.235 7.495 22.405 7.665 ;
        RECT 22.605 7.495 22.775 7.665 ;
        RECT 23.345 7.495 23.515 7.665 ;
        RECT 23.715 7.495 23.885 7.665 ;
        RECT 24.085 7.495 24.255 7.665 ;
        RECT 24.455 7.495 24.625 7.665 ;
        RECT 24.825 7.495 24.995 7.665 ;
        RECT 25.195 7.495 25.365 7.665 ;
        RECT 25.565 7.495 25.735 7.665 ;
        RECT 25.935 7.495 26.105 7.665 ;
        RECT 26.675 7.495 26.845 7.665 ;
        RECT 27.045 7.495 27.215 7.665 ;
        RECT 27.415 7.495 27.585 7.665 ;
        RECT 27.785 7.495 27.955 7.665 ;
        RECT 28.155 7.495 28.325 7.665 ;
        RECT 28.525 7.495 28.695 7.665 ;
        RECT 28.895 7.495 29.065 7.665 ;
        RECT 29.265 7.495 29.435 7.665 ;
        RECT 29.635 7.495 29.805 7.665 ;
        RECT 30.005 7.495 30.175 7.665 ;
        RECT 30.375 7.495 30.545 7.665 ;
        RECT 30.745 7.495 30.915 7.665 ;
        RECT 31.485 7.495 31.655 7.665 ;
        RECT 31.855 7.495 32.025 7.665 ;
        RECT 32.225 7.495 32.395 7.665 ;
        RECT 32.595 7.495 32.765 7.665 ;
        RECT 32.965 7.495 33.135 7.665 ;
        RECT 33.335 7.495 33.505 7.665 ;
        RECT 33.705 7.495 33.875 7.665 ;
        RECT 34.075 7.495 34.245 7.665 ;
        RECT 34.445 7.495 34.615 7.665 ;
        RECT 34.815 7.495 34.985 7.665 ;
        RECT 35.185 7.495 35.355 7.665 ;
        RECT 35.555 7.495 35.725 7.665 ;
        RECT 36.295 7.495 36.465 7.665 ;
        RECT 36.665 7.495 36.835 7.665 ;
        RECT 37.035 7.495 37.205 7.665 ;
        RECT 37.405 7.495 37.575 7.665 ;
        RECT 37.775 7.495 37.945 7.665 ;
        RECT 38.145 7.495 38.315 7.665 ;
        RECT 38.515 7.495 38.685 7.665 ;
        RECT 38.885 7.495 39.055 7.665 ;
        RECT 39.625 7.495 39.795 7.665 ;
        RECT 39.995 7.495 40.165 7.665 ;
        RECT 40.365 7.495 40.535 7.665 ;
        RECT 40.735 7.495 40.905 7.665 ;
        RECT 41.105 7.495 41.275 7.665 ;
        RECT 41.475 7.495 41.645 7.665 ;
        RECT 41.845 7.495 42.015 7.665 ;
        RECT 42.215 7.495 42.385 7.665 ;
        RECT 42.585 7.495 42.755 7.665 ;
        RECT 42.955 7.495 43.125 7.665 ;
        RECT 43.325 7.495 43.495 7.665 ;
        RECT 43.695 7.495 43.865 7.665 ;
        RECT 44.435 7.495 44.605 7.665 ;
        RECT 44.805 7.495 44.975 7.665 ;
        RECT 45.175 7.495 45.345 7.665 ;
        RECT 45.545 7.495 45.715 7.665 ;
        RECT 45.915 7.495 46.085 7.665 ;
        RECT 46.285 7.495 46.455 7.665 ;
        RECT 46.655 7.495 46.825 7.665 ;
        RECT 47.025 7.495 47.195 7.665 ;
        RECT 47.395 7.495 47.565 7.665 ;
        RECT 47.765 7.495 47.935 7.665 ;
        RECT 48.135 7.495 48.305 7.665 ;
        RECT 48.505 7.495 48.675 7.665 ;
        RECT 49.245 7.495 49.415 7.665 ;
        RECT 49.615 7.495 49.785 7.665 ;
        RECT 49.985 7.495 50.155 7.665 ;
        RECT 50.355 7.495 50.525 7.665 ;
        RECT 50.725 7.495 50.895 7.665 ;
        RECT 51.095 7.495 51.265 7.665 ;
        RECT 51.465 7.495 51.635 7.665 ;
        RECT 51.835 7.495 52.005 7.665 ;
        RECT 52.575 7.495 52.745 7.665 ;
        RECT 52.945 7.495 53.115 7.665 ;
        RECT 53.315 7.495 53.485 7.665 ;
        RECT 53.685 7.495 53.855 7.665 ;
        RECT 54.055 7.495 54.225 7.665 ;
        RECT 54.425 7.495 54.595 7.665 ;
        RECT 54.795 7.495 54.965 7.665 ;
        RECT 55.165 7.495 55.335 7.665 ;
        RECT 55.535 7.495 55.705 7.665 ;
        RECT 55.905 7.495 56.075 7.665 ;
        RECT 56.275 7.495 56.445 7.665 ;
        RECT 56.645 7.495 56.815 7.665 ;
        RECT 57.385 7.495 57.555 7.665 ;
        RECT 57.755 7.495 57.925 7.665 ;
        RECT 58.125 7.495 58.295 7.665 ;
        RECT 58.495 7.495 58.665 7.665 ;
        RECT 58.865 7.495 59.035 7.665 ;
        RECT 59.235 7.495 59.405 7.665 ;
        RECT 59.605 7.495 59.775 7.665 ;
        RECT 59.975 7.495 60.145 7.665 ;
        RECT 60.345 7.495 60.515 7.665 ;
        RECT 60.715 7.495 60.885 7.665 ;
        RECT 61.085 7.495 61.255 7.665 ;
        RECT 61.455 7.495 61.625 7.665 ;
        RECT 62.195 7.495 62.365 7.665 ;
        RECT 62.565 7.495 62.735 7.665 ;
        RECT 62.935 7.495 63.105 7.665 ;
        RECT 63.305 7.495 63.475 7.665 ;
        RECT 63.675 7.495 63.845 7.665 ;
        RECT 64.045 7.495 64.215 7.665 ;
        RECT 64.415 7.495 64.585 7.665 ;
        RECT 64.785 7.495 64.955 7.665 ;
        RECT 65.525 7.495 65.695 7.665 ;
        RECT 65.895 7.495 66.065 7.665 ;
        RECT 66.265 7.495 66.435 7.665 ;
        RECT 66.635 7.495 66.805 7.665 ;
        RECT 67.005 7.495 67.175 7.665 ;
        RECT 67.375 7.495 67.545 7.665 ;
        RECT 67.745 7.495 67.915 7.665 ;
        RECT 68.115 7.495 68.285 7.665 ;
        RECT 68.485 7.495 68.655 7.665 ;
        RECT 68.855 7.495 69.025 7.665 ;
        RECT 69.225 7.495 69.395 7.665 ;
        RECT 69.595 7.495 69.765 7.665 ;
        RECT 70.335 7.495 70.505 7.665 ;
        RECT 70.705 7.495 70.875 7.665 ;
        RECT 71.075 7.495 71.245 7.665 ;
        RECT 71.445 7.495 71.615 7.665 ;
        RECT 71.815 7.495 71.985 7.665 ;
        RECT 72.185 7.495 72.355 7.665 ;
        RECT 72.555 7.495 72.725 7.665 ;
        RECT 72.925 7.495 73.095 7.665 ;
        RECT 73.295 7.495 73.465 7.665 ;
        RECT 73.665 7.495 73.835 7.665 ;
        RECT 74.035 7.495 74.205 7.665 ;
        RECT 74.405 7.495 74.575 7.665 ;
        RECT 75.145 7.495 75.315 7.665 ;
        RECT 75.515 7.495 75.685 7.665 ;
        RECT 75.885 7.495 76.055 7.665 ;
        RECT 76.255 7.495 76.425 7.665 ;
        RECT 76.625 7.495 76.795 7.665 ;
        RECT 76.995 7.495 77.165 7.665 ;
        RECT 77.365 7.495 77.535 7.665 ;
        RECT 77.735 7.495 77.905 7.665 ;
        RECT 78.475 7.495 78.645 7.665 ;
        RECT 78.845 7.495 79.015 7.665 ;
        RECT 79.215 7.495 79.385 7.665 ;
        RECT 79.585 7.495 79.755 7.665 ;
        RECT 79.955 7.495 80.125 7.665 ;
        RECT 80.325 7.495 80.495 7.665 ;
        RECT 80.695 7.495 80.865 7.665 ;
        RECT 81.065 7.495 81.235 7.665 ;
        RECT 81.805 7.495 81.975 7.665 ;
        RECT 82.175 7.495 82.345 7.665 ;
        RECT 82.545 7.495 82.715 7.665 ;
        RECT 82.915 7.495 83.085 7.665 ;
        RECT 83.285 7.495 83.455 7.665 ;
        RECT 83.655 7.495 83.825 7.665 ;
        RECT 84.025 7.495 84.195 7.665 ;
        RECT 84.395 7.495 84.565 7.665 ;
        RECT 85.135 7.495 85.305 7.665 ;
        RECT 85.505 7.495 85.675 7.665 ;
        RECT 85.875 7.495 86.045 7.665 ;
        RECT 86.245 7.495 86.415 7.665 ;
        RECT 86.615 7.495 86.785 7.665 ;
        RECT 86.985 7.495 87.155 7.665 ;
        RECT 87.355 7.495 87.525 7.665 ;
        RECT 87.725 7.495 87.895 7.665 ;
        RECT 88.465 7.495 88.635 7.665 ;
        RECT 88.835 7.495 89.005 7.665 ;
        RECT 89.205 7.495 89.375 7.665 ;
        RECT 89.575 7.495 89.745 7.665 ;
        RECT 89.945 7.495 90.115 7.665 ;
        RECT 1.515 4.165 1.685 4.335 ;
        RECT 2.625 4.535 2.795 4.705 ;
        RECT 3.735 3.425 3.905 3.595 ;
        RECT 4.475 3.795 4.645 3.965 ;
        RECT 6.325 3.795 6.495 3.965 ;
        RECT 7.435 2.685 7.605 2.855 ;
        RECT 9.285 3.425 9.455 3.595 ;
        RECT 11.135 3.425 11.305 3.595 ;
        RECT 11.875 4.165 12.045 4.335 ;
        RECT 12.615 3.425 12.785 3.595 ;
        RECT 14.465 3.425 14.635 3.595 ;
        RECT 16.685 2.315 16.855 2.485 ;
        RECT 17.425 4.165 17.595 4.335 ;
        RECT 19.275 3.795 19.445 3.965 ;
        RECT 20.385 2.315 20.555 2.485 ;
        RECT 21.495 3.055 21.665 3.225 ;
        RECT 22.235 4.165 22.405 4.335 ;
        RECT 24.085 4.165 24.255 4.335 ;
        RECT 24.825 4.165 24.995 4.335 ;
        RECT 25.565 3.055 25.735 3.225 ;
        RECT 27.415 4.165 27.585 4.335 ;
        RECT 29.635 3.425 29.805 3.595 ;
        RECT 30.375 3.795 30.545 3.965 ;
        RECT 32.225 3.795 32.395 3.965 ;
        RECT 33.335 2.685 33.505 2.855 ;
        RECT 34.445 2.315 34.615 2.485 ;
        RECT 35.185 3.425 35.355 3.595 ;
        RECT 37.035 3.425 37.205 3.595 ;
        RECT 37.775 4.165 37.945 4.335 ;
        RECT 38.515 3.425 38.685 3.595 ;
        RECT 40.365 3.425 40.535 3.595 ;
        RECT 42.585 2.315 42.755 2.485 ;
        RECT 43.325 4.165 43.495 4.335 ;
        RECT 45.175 3.795 45.345 3.965 ;
        RECT 46.285 2.315 46.455 2.485 ;
        RECT 47.395 3.425 47.565 3.595 ;
        RECT 48.135 3.795 48.305 3.965 ;
        RECT 49.985 3.795 50.155 3.965 ;
        RECT 50.725 4.165 50.895 4.335 ;
        RECT 51.465 3.425 51.635 3.595 ;
        RECT 53.315 4.165 53.485 4.335 ;
        RECT 55.535 3.425 55.705 3.595 ;
        RECT 56.275 3.795 56.445 3.965 ;
        RECT 58.125 3.795 58.295 3.965 ;
        RECT 59.235 2.685 59.405 2.855 ;
        RECT 60.345 2.315 60.515 2.485 ;
        RECT 61.085 3.425 61.255 3.595 ;
        RECT 62.935 3.425 63.105 3.595 ;
        RECT 63.675 4.165 63.845 4.335 ;
        RECT 64.415 3.425 64.585 3.595 ;
        RECT 66.265 3.425 66.435 3.595 ;
        RECT 68.485 2.315 68.655 2.485 ;
        RECT 69.225 4.165 69.395 4.335 ;
        RECT 71.075 3.795 71.245 3.965 ;
        RECT 72.185 2.315 72.355 2.485 ;
        RECT 73.295 3.795 73.465 3.965 ;
        RECT 74.035 4.165 74.205 4.335 ;
        RECT 75.885 4.165 76.055 4.335 ;
        RECT 76.625 4.165 76.795 4.335 ;
        RECT 80.215 5.305 80.385 5.475 ;
        RECT 78.845 4.535 79.015 4.705 ;
        RECT 77.365 3.795 77.535 3.965 ;
        RECT 78.845 3.425 79.015 3.595 ;
        RECT 79.955 4.165 80.125 4.335 ;
        RECT 82.215 5.305 82.385 5.475 ;
        RECT 83.535 5.305 83.705 5.475 ;
        RECT 82.545 4.535 82.715 4.705 ;
        RECT 79.955 3.795 80.125 3.965 ;
        RECT 80.255 1.275 80.425 1.445 ;
        RECT 85.555 5.305 85.725 5.475 ;
        RECT 84.025 3.055 84.195 3.225 ;
        RECT 84.025 2.175 84.195 2.345 ;
        RECT 83.585 1.275 83.755 1.445 ;
        RECT 85.505 2.175 85.675 2.345 ;
        RECT 86.615 4.165 86.785 4.335 ;
        RECT 87.355 4.165 87.525 4.335 ;
        RECT 88.835 4.165 89.005 4.335 ;
        RECT 86.915 1.275 87.085 1.445 ;
        RECT 0.775 0.095 0.945 0.265 ;
        RECT 1.145 0.095 1.315 0.265 ;
        RECT 1.515 0.095 1.685 0.265 ;
        RECT 1.885 0.095 2.055 0.265 ;
        RECT 2.255 0.095 2.425 0.265 ;
        RECT 2.625 0.095 2.795 0.265 ;
        RECT 2.995 0.095 3.165 0.265 ;
        RECT 3.365 0.095 3.535 0.265 ;
        RECT 3.735 0.095 3.905 0.265 ;
        RECT 4.105 0.095 4.275 0.265 ;
        RECT 4.475 0.095 4.645 0.265 ;
        RECT 4.845 0.095 5.015 0.265 ;
        RECT 5.585 0.095 5.755 0.265 ;
        RECT 5.955 0.095 6.125 0.265 ;
        RECT 6.325 0.095 6.495 0.265 ;
        RECT 6.695 0.095 6.865 0.265 ;
        RECT 7.065 0.095 7.235 0.265 ;
        RECT 7.435 0.095 7.605 0.265 ;
        RECT 7.805 0.095 7.975 0.265 ;
        RECT 8.175 0.095 8.345 0.265 ;
        RECT 8.545 0.095 8.715 0.265 ;
        RECT 8.915 0.095 9.085 0.265 ;
        RECT 9.285 0.095 9.455 0.265 ;
        RECT 9.655 0.095 9.825 0.265 ;
        RECT 10.395 0.095 10.565 0.265 ;
        RECT 10.765 0.095 10.935 0.265 ;
        RECT 11.135 0.095 11.305 0.265 ;
        RECT 11.505 0.095 11.675 0.265 ;
        RECT 11.875 0.095 12.045 0.265 ;
        RECT 12.245 0.095 12.415 0.265 ;
        RECT 12.615 0.095 12.785 0.265 ;
        RECT 12.985 0.095 13.155 0.265 ;
        RECT 13.725 0.095 13.895 0.265 ;
        RECT 14.095 0.095 14.265 0.265 ;
        RECT 14.465 0.095 14.635 0.265 ;
        RECT 14.835 0.095 15.005 0.265 ;
        RECT 15.205 0.095 15.375 0.265 ;
        RECT 15.575 0.095 15.745 0.265 ;
        RECT 15.945 0.095 16.115 0.265 ;
        RECT 16.315 0.095 16.485 0.265 ;
        RECT 16.685 0.095 16.855 0.265 ;
        RECT 17.055 0.095 17.225 0.265 ;
        RECT 17.425 0.095 17.595 0.265 ;
        RECT 17.795 0.095 17.965 0.265 ;
        RECT 18.535 0.095 18.705 0.265 ;
        RECT 18.905 0.095 19.075 0.265 ;
        RECT 19.275 0.095 19.445 0.265 ;
        RECT 19.645 0.095 19.815 0.265 ;
        RECT 20.015 0.095 20.185 0.265 ;
        RECT 20.385 0.095 20.555 0.265 ;
        RECT 20.755 0.095 20.925 0.265 ;
        RECT 21.125 0.095 21.295 0.265 ;
        RECT 21.495 0.095 21.665 0.265 ;
        RECT 21.865 0.095 22.035 0.265 ;
        RECT 22.235 0.095 22.405 0.265 ;
        RECT 22.605 0.095 22.775 0.265 ;
        RECT 23.345 0.095 23.515 0.265 ;
        RECT 23.715 0.095 23.885 0.265 ;
        RECT 24.085 0.095 24.255 0.265 ;
        RECT 24.455 0.095 24.625 0.265 ;
        RECT 24.825 0.095 24.995 0.265 ;
        RECT 25.195 0.095 25.365 0.265 ;
        RECT 25.565 0.095 25.735 0.265 ;
        RECT 25.935 0.095 26.105 0.265 ;
        RECT 26.675 0.095 26.845 0.265 ;
        RECT 27.045 0.095 27.215 0.265 ;
        RECT 27.415 0.095 27.585 0.265 ;
        RECT 27.785 0.095 27.955 0.265 ;
        RECT 28.155 0.095 28.325 0.265 ;
        RECT 28.525 0.095 28.695 0.265 ;
        RECT 28.895 0.095 29.065 0.265 ;
        RECT 29.265 0.095 29.435 0.265 ;
        RECT 29.635 0.095 29.805 0.265 ;
        RECT 30.005 0.095 30.175 0.265 ;
        RECT 30.375 0.095 30.545 0.265 ;
        RECT 30.745 0.095 30.915 0.265 ;
        RECT 31.485 0.095 31.655 0.265 ;
        RECT 31.855 0.095 32.025 0.265 ;
        RECT 32.225 0.095 32.395 0.265 ;
        RECT 32.595 0.095 32.765 0.265 ;
        RECT 32.965 0.095 33.135 0.265 ;
        RECT 33.335 0.095 33.505 0.265 ;
        RECT 33.705 0.095 33.875 0.265 ;
        RECT 34.075 0.095 34.245 0.265 ;
        RECT 34.445 0.095 34.615 0.265 ;
        RECT 34.815 0.095 34.985 0.265 ;
        RECT 35.185 0.095 35.355 0.265 ;
        RECT 35.555 0.095 35.725 0.265 ;
        RECT 36.295 0.095 36.465 0.265 ;
        RECT 36.665 0.095 36.835 0.265 ;
        RECT 37.035 0.095 37.205 0.265 ;
        RECT 37.405 0.095 37.575 0.265 ;
        RECT 37.775 0.095 37.945 0.265 ;
        RECT 38.145 0.095 38.315 0.265 ;
        RECT 38.515 0.095 38.685 0.265 ;
        RECT 38.885 0.095 39.055 0.265 ;
        RECT 39.625 0.095 39.795 0.265 ;
        RECT 39.995 0.095 40.165 0.265 ;
        RECT 40.365 0.095 40.535 0.265 ;
        RECT 40.735 0.095 40.905 0.265 ;
        RECT 41.105 0.095 41.275 0.265 ;
        RECT 41.475 0.095 41.645 0.265 ;
        RECT 41.845 0.095 42.015 0.265 ;
        RECT 42.215 0.095 42.385 0.265 ;
        RECT 42.585 0.095 42.755 0.265 ;
        RECT 42.955 0.095 43.125 0.265 ;
        RECT 43.325 0.095 43.495 0.265 ;
        RECT 43.695 0.095 43.865 0.265 ;
        RECT 44.435 0.095 44.605 0.265 ;
        RECT 44.805 0.095 44.975 0.265 ;
        RECT 45.175 0.095 45.345 0.265 ;
        RECT 45.545 0.095 45.715 0.265 ;
        RECT 45.915 0.095 46.085 0.265 ;
        RECT 46.285 0.095 46.455 0.265 ;
        RECT 46.655 0.095 46.825 0.265 ;
        RECT 47.025 0.095 47.195 0.265 ;
        RECT 47.395 0.095 47.565 0.265 ;
        RECT 47.765 0.095 47.935 0.265 ;
        RECT 48.135 0.095 48.305 0.265 ;
        RECT 48.505 0.095 48.675 0.265 ;
        RECT 49.245 0.095 49.415 0.265 ;
        RECT 49.615 0.095 49.785 0.265 ;
        RECT 49.985 0.095 50.155 0.265 ;
        RECT 50.355 0.095 50.525 0.265 ;
        RECT 50.725 0.095 50.895 0.265 ;
        RECT 51.095 0.095 51.265 0.265 ;
        RECT 51.465 0.095 51.635 0.265 ;
        RECT 51.835 0.095 52.005 0.265 ;
        RECT 52.575 0.095 52.745 0.265 ;
        RECT 52.945 0.095 53.115 0.265 ;
        RECT 53.315 0.095 53.485 0.265 ;
        RECT 53.685 0.095 53.855 0.265 ;
        RECT 54.055 0.095 54.225 0.265 ;
        RECT 54.425 0.095 54.595 0.265 ;
        RECT 54.795 0.095 54.965 0.265 ;
        RECT 55.165 0.095 55.335 0.265 ;
        RECT 55.535 0.095 55.705 0.265 ;
        RECT 55.905 0.095 56.075 0.265 ;
        RECT 56.275 0.095 56.445 0.265 ;
        RECT 56.645 0.095 56.815 0.265 ;
        RECT 57.385 0.095 57.555 0.265 ;
        RECT 57.755 0.095 57.925 0.265 ;
        RECT 58.125 0.095 58.295 0.265 ;
        RECT 58.495 0.095 58.665 0.265 ;
        RECT 58.865 0.095 59.035 0.265 ;
        RECT 59.235 0.095 59.405 0.265 ;
        RECT 59.605 0.095 59.775 0.265 ;
        RECT 59.975 0.095 60.145 0.265 ;
        RECT 60.345 0.095 60.515 0.265 ;
        RECT 60.715 0.095 60.885 0.265 ;
        RECT 61.085 0.095 61.255 0.265 ;
        RECT 61.455 0.095 61.625 0.265 ;
        RECT 62.195 0.095 62.365 0.265 ;
        RECT 62.565 0.095 62.735 0.265 ;
        RECT 62.935 0.095 63.105 0.265 ;
        RECT 63.305 0.095 63.475 0.265 ;
        RECT 63.675 0.095 63.845 0.265 ;
        RECT 64.045 0.095 64.215 0.265 ;
        RECT 64.415 0.095 64.585 0.265 ;
        RECT 64.785 0.095 64.955 0.265 ;
        RECT 65.525 0.095 65.695 0.265 ;
        RECT 65.895 0.095 66.065 0.265 ;
        RECT 66.265 0.095 66.435 0.265 ;
        RECT 66.635 0.095 66.805 0.265 ;
        RECT 67.005 0.095 67.175 0.265 ;
        RECT 67.375 0.095 67.545 0.265 ;
        RECT 67.745 0.095 67.915 0.265 ;
        RECT 68.115 0.095 68.285 0.265 ;
        RECT 68.485 0.095 68.655 0.265 ;
        RECT 68.855 0.095 69.025 0.265 ;
        RECT 69.225 0.095 69.395 0.265 ;
        RECT 69.595 0.095 69.765 0.265 ;
        RECT 70.335 0.095 70.505 0.265 ;
        RECT 70.705 0.095 70.875 0.265 ;
        RECT 71.075 0.095 71.245 0.265 ;
        RECT 71.445 0.095 71.615 0.265 ;
        RECT 71.815 0.095 71.985 0.265 ;
        RECT 72.185 0.095 72.355 0.265 ;
        RECT 72.555 0.095 72.725 0.265 ;
        RECT 72.925 0.095 73.095 0.265 ;
        RECT 73.295 0.095 73.465 0.265 ;
        RECT 73.665 0.095 73.835 0.265 ;
        RECT 74.035 0.095 74.205 0.265 ;
        RECT 74.405 0.095 74.575 0.265 ;
        RECT 75.145 0.095 75.315 0.265 ;
        RECT 75.515 0.095 75.685 0.265 ;
        RECT 75.885 0.095 76.055 0.265 ;
        RECT 76.255 0.095 76.425 0.265 ;
        RECT 76.625 0.095 76.795 0.265 ;
        RECT 76.995 0.095 77.165 0.265 ;
        RECT 77.365 0.095 77.535 0.265 ;
        RECT 77.735 0.095 77.905 0.265 ;
        RECT 78.475 0.095 78.645 0.265 ;
        RECT 78.845 0.095 79.015 0.265 ;
        RECT 79.215 0.095 79.385 0.265 ;
        RECT 79.585 0.095 79.755 0.265 ;
        RECT 79.955 0.095 80.125 0.265 ;
        RECT 80.325 0.095 80.495 0.265 ;
        RECT 80.695 0.095 80.865 0.265 ;
        RECT 81.065 0.095 81.235 0.265 ;
        RECT 81.805 0.095 81.975 0.265 ;
        RECT 82.175 0.095 82.345 0.265 ;
        RECT 82.545 0.095 82.715 0.265 ;
        RECT 82.915 0.095 83.085 0.265 ;
        RECT 83.285 0.095 83.455 0.265 ;
        RECT 83.655 0.095 83.825 0.265 ;
        RECT 84.025 0.095 84.195 0.265 ;
        RECT 84.395 0.095 84.565 0.265 ;
        RECT 85.135 0.095 85.305 0.265 ;
        RECT 85.505 0.095 85.675 0.265 ;
        RECT 85.875 0.095 86.045 0.265 ;
        RECT 86.245 0.095 86.415 0.265 ;
        RECT 86.615 0.095 86.785 0.265 ;
        RECT 86.985 0.095 87.155 0.265 ;
        RECT 87.355 0.095 87.525 0.265 ;
        RECT 87.725 0.095 87.895 0.265 ;
        RECT 88.465 0.095 88.635 0.265 ;
        RECT 88.835 0.095 89.005 0.265 ;
        RECT 89.205 0.095 89.375 0.265 ;
        RECT 89.575 0.095 89.745 0.265 ;
        RECT 89.945 0.095 90.115 0.265 ;
      LAYER met1 ;
        RECT 80.185 5.475 80.415 5.505 ;
        RECT 82.185 5.475 82.415 5.505 ;
        RECT 83.505 5.475 83.735 5.505 ;
        RECT 85.525 5.475 85.755 5.505 ;
        RECT 80.155 5.305 82.445 5.475 ;
        RECT 83.475 5.305 85.785 5.475 ;
        RECT 80.185 5.275 80.415 5.305 ;
        RECT 82.185 5.275 82.415 5.305 ;
        RECT 83.505 5.275 83.735 5.305 ;
        RECT 85.525 5.275 85.755 5.305 ;
        RECT 78.815 4.705 79.045 4.735 ;
        RECT 82.515 4.705 82.745 4.735 ;
        RECT 78.785 4.535 82.775 4.705 ;
        RECT 78.815 4.505 79.045 4.535 ;
        RECT 82.515 4.505 82.745 4.535 ;
        RECT 1.485 4.335 1.715 4.365 ;
        RECT 11.845 4.335 12.075 4.365 ;
        RECT 17.395 4.335 17.625 4.365 ;
        RECT 22.205 4.335 22.435 4.365 ;
        RECT 24.055 4.335 24.285 4.365 ;
        RECT 24.795 4.335 25.025 4.365 ;
        RECT 27.385 4.335 27.615 4.365 ;
        RECT 37.745 4.335 37.975 4.365 ;
        RECT 43.295 4.335 43.525 4.365 ;
        RECT 50.695 4.335 50.925 4.365 ;
        RECT 53.285 4.335 53.515 4.365 ;
        RECT 63.645 4.335 63.875 4.365 ;
        RECT 69.195 4.335 69.425 4.365 ;
        RECT 74.005 4.335 74.235 4.365 ;
        RECT 75.855 4.335 76.085 4.365 ;
        RECT 76.595 4.335 76.825 4.365 ;
        RECT 79.925 4.335 80.155 4.365 ;
        RECT 86.585 4.335 86.815 4.365 ;
        RECT 87.325 4.335 87.555 4.365 ;
        RECT 88.805 4.335 89.035 4.365 ;
        RECT 1.455 4.165 25.055 4.335 ;
        RECT 27.355 4.165 50.955 4.335 ;
        RECT 53.255 4.165 76.855 4.335 ;
        RECT 79.895 4.165 86.845 4.335 ;
        RECT 87.295 4.165 89.065 4.335 ;
        RECT 1.485 4.135 1.715 4.165 ;
        RECT 11.845 4.135 12.075 4.165 ;
        RECT 17.395 4.135 17.625 4.165 ;
        RECT 22.205 4.135 22.435 4.165 ;
        RECT 24.055 4.135 24.285 4.165 ;
        RECT 24.795 4.135 25.025 4.165 ;
        RECT 27.385 4.135 27.615 4.165 ;
        RECT 37.745 4.135 37.975 4.165 ;
        RECT 43.295 4.135 43.525 4.165 ;
        RECT 50.695 4.135 50.925 4.165 ;
        RECT 53.285 4.135 53.515 4.165 ;
        RECT 63.645 4.135 63.875 4.165 ;
        RECT 69.195 4.135 69.425 4.165 ;
        RECT 74.005 4.135 74.235 4.165 ;
        RECT 75.855 4.135 76.085 4.165 ;
        RECT 76.595 4.135 76.825 4.165 ;
        RECT 79.925 4.135 80.155 4.165 ;
        RECT 86.585 4.135 86.815 4.165 ;
        RECT 87.325 4.135 87.555 4.165 ;
        RECT 88.805 4.135 89.035 4.165 ;
        RECT 4.445 3.965 4.675 3.995 ;
        RECT 6.295 3.965 6.525 3.995 ;
        RECT 19.245 3.965 19.475 3.995 ;
        RECT 30.345 3.965 30.575 3.995 ;
        RECT 32.195 3.965 32.425 3.995 ;
        RECT 45.145 3.965 45.375 3.995 ;
        RECT 48.105 3.965 48.335 3.995 ;
        RECT 49.955 3.965 50.185 3.995 ;
        RECT 56.245 3.965 56.475 3.995 ;
        RECT 58.095 3.965 58.325 3.995 ;
        RECT 71.045 3.965 71.275 3.995 ;
        RECT 73.265 3.965 73.495 3.995 ;
        RECT 77.335 3.965 77.565 3.995 ;
        RECT 79.925 3.965 80.155 3.995 ;
        RECT 4.415 3.795 19.505 3.965 ;
        RECT 30.315 3.795 45.405 3.965 ;
        RECT 48.075 3.795 50.215 3.965 ;
        RECT 56.215 3.795 71.305 3.965 ;
        RECT 73.235 3.795 80.185 3.965 ;
        RECT 4.445 3.765 4.675 3.795 ;
        RECT 6.295 3.765 6.525 3.795 ;
        RECT 19.245 3.765 19.475 3.795 ;
        RECT 30.345 3.765 30.575 3.795 ;
        RECT 32.195 3.765 32.425 3.795 ;
        RECT 45.145 3.765 45.375 3.795 ;
        RECT 48.105 3.765 48.335 3.795 ;
        RECT 49.955 3.765 50.185 3.795 ;
        RECT 56.245 3.765 56.475 3.795 ;
        RECT 58.095 3.765 58.325 3.795 ;
        RECT 71.045 3.765 71.275 3.795 ;
        RECT 73.265 3.765 73.495 3.795 ;
        RECT 77.335 3.765 77.565 3.795 ;
        RECT 79.925 3.765 80.155 3.795 ;
        RECT 3.705 3.595 3.935 3.625 ;
        RECT 9.255 3.595 9.485 3.625 ;
        RECT 11.105 3.595 11.335 3.625 ;
        RECT 12.585 3.595 12.815 3.625 ;
        RECT 14.435 3.595 14.665 3.625 ;
        RECT 29.605 3.595 29.835 3.625 ;
        RECT 35.155 3.595 35.385 3.625 ;
        RECT 37.005 3.595 37.235 3.625 ;
        RECT 38.485 3.595 38.715 3.625 ;
        RECT 40.335 3.595 40.565 3.625 ;
        RECT 47.365 3.595 47.595 3.625 ;
        RECT 51.435 3.595 51.665 3.625 ;
        RECT 55.505 3.595 55.735 3.625 ;
        RECT 61.055 3.595 61.285 3.625 ;
        RECT 62.905 3.595 63.135 3.625 ;
        RECT 64.385 3.595 64.615 3.625 ;
        RECT 66.235 3.595 66.465 3.625 ;
        RECT 78.815 3.595 79.045 3.625 ;
        RECT 3.675 3.425 11.365 3.595 ;
        RECT 12.555 3.425 14.695 3.595 ;
        RECT 29.575 3.425 37.265 3.595 ;
        RECT 38.455 3.425 40.595 3.595 ;
        RECT 47.335 3.425 79.075 3.595 ;
        RECT 3.705 3.395 3.935 3.425 ;
        RECT 9.255 3.395 9.485 3.425 ;
        RECT 11.105 3.395 11.335 3.425 ;
        RECT 12.585 3.395 12.815 3.425 ;
        RECT 14.435 3.395 14.665 3.425 ;
        RECT 29.605 3.395 29.835 3.425 ;
        RECT 35.155 3.395 35.385 3.425 ;
        RECT 37.005 3.395 37.235 3.425 ;
        RECT 38.485 3.395 38.715 3.425 ;
        RECT 40.335 3.395 40.565 3.425 ;
        RECT 47.365 3.395 47.595 3.425 ;
        RECT 51.435 3.395 51.665 3.425 ;
        RECT 55.505 3.395 55.735 3.425 ;
        RECT 61.055 3.395 61.285 3.425 ;
        RECT 62.905 3.395 63.135 3.425 ;
        RECT 64.385 3.395 64.615 3.425 ;
        RECT 66.235 3.395 66.465 3.425 ;
        RECT 78.815 3.395 79.045 3.425 ;
        RECT 21.465 3.225 21.695 3.255 ;
        RECT 25.535 3.225 25.765 3.255 ;
        RECT 83.995 3.225 84.225 3.255 ;
        RECT 21.435 3.055 84.255 3.225 ;
        RECT 21.465 3.025 21.695 3.055 ;
        RECT 25.535 3.025 25.765 3.055 ;
        RECT 83.995 3.025 84.225 3.055 ;
        RECT 83.995 2.345 84.225 2.375 ;
        RECT 85.475 2.345 85.705 2.375 ;
        RECT 83.965 2.175 85.735 2.345 ;
        RECT 83.995 2.145 84.225 2.175 ;
        RECT 85.475 2.145 85.705 2.175 ;
        RECT 80.225 1.445 80.455 1.475 ;
        RECT 83.555 1.445 83.785 1.475 ;
        RECT 86.885 1.445 87.115 1.475 ;
        RECT 80.195 1.275 87.145 1.445 ;
        RECT 80.225 1.245 80.455 1.275 ;
        RECT 83.555 1.245 83.785 1.275 ;
        RECT 86.885 1.245 87.115 1.275 ;
  END
END TMRDFFRNQX1
END LIBRARY

